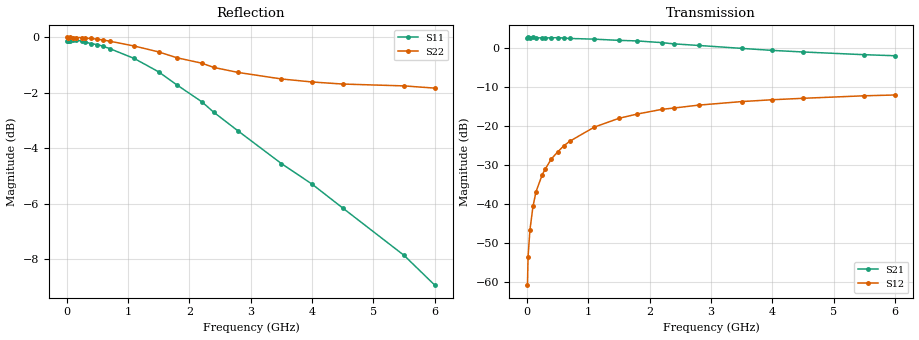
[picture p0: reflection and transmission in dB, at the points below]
! SIEMENS Discrete & RF Semiconductors
! BFY180
! Si NPN RF Bipolar Junction Transistor in MICRO-X
! VCE = 5 V  IC = 0.4 mA
! Common Emitter S-Parameters:  May  1997
# GHz  S  MA  R  50
!  f  S11  S21  S12  S22
! GHz  MAG  ANG  MAG  ANG  MAG  ANG  MAG  ANG
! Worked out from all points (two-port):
!   36 points, 10 MHz to 6 GHz, reference 50 ohm
!   highest |S21| = 2.85 dB at 100 MHz (marker M1); lowest = -1.9 dB at 6 GHz (marker M2)
!   |S21| within 3 dB of the highest: start of sweep to 3.664 GHz
!   lowest |S11| = -8.9 dB at 6 GHz (marker M3), VSWR 2.11, Z = 27.7 - j17.8 ohm
!   |S11| at or under -10 dB: nowhere
!   |S22| runs from -1.8 to 0.0 dB; largest |S21 - S12| = 1.4
!   S11 on the Smith chart (normalised r, x): 10 MHz: open; 700 MHz: 0.71, -5.36; 1.5 GHz: 0.52, -2.45; 2.4 GHz: 0.50, -1.44; 4 GHz: 0.51, -0.79; 6 GHz: 0.55, -0.36
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0.01  0.9844 -0.3  1.378 179.7  0.0009 80.4  0.9995 -0.1
0.02  0.9862 -0.6  1.386 179.0  0.0021 92.9  0.9991 -0.4
0.05  0.9845 -1.5  1.374 178.1  0.0046 87.4  0.9996 -1.1
0.1  0.9873 -3.0  1.388 176.4  0.0093 88.4  0.9979 -2.2
0.15  0.99 -4.6  1.367 174.4  0.0144 87.1  0.999 -3.3
0.25  0.9836 -7.6  1.371 170.7  0.0236 84.2  0.9989 -5.5
0.3  0.9808 -8.8  1.367 168.3  0.0281 83.5  0.9961 -6.5
0.4  0.9737 -11.8  1.369 164.4  0.0379 80.7  0.9953 -8.5
0.5  0.9703 -14.9  1.378 160.4  0.0464 78.2  0.992 -10.8
0.6  0.9631 -17.7  1.36 156.2  0.0556 75.9  0.9889 -12.9
0.7  0.9543 -20.8  1.345 153.1  0.064 73.3  0.984 -15.1
1.1  0.9161 -31.9  1.317 138.4  0.0972 64.2  0.9646 -23.3
1.5  0.8664 -42.9  1.271 124.4  0.1261 55.4  0.9411 -31.2
1.8  0.8202 -51.3  1.249 113.9  0.1433 49.8  0.9184 -36.7
2.2  0.7657 -60.5  1.189 100.8  0.1644 42.4  0.8983 -43.6
2.4  0.7324 -65.2  1.145 94.6  0.1713 39.1  0.8823 -46.8
2.8  0.6772 -73.3  1.093 83.4  0.1865 33.3  0.8641 -52.7
3.5  0.5922 -85.9  1.002 65.1  0.2071 24.4  0.8412 -62.4
4  0.5437 -94.2  0.944 53.6  0.2187 18.7  0.8307 -69.2
4.5  0.4924 -102.0  0.901 43.4  0.2283 13.7  0.8236 -76.0
5.5  0.4045 -118.6  0.831 24.0  0.2459 3.8  0.8173 -90.0
6  0.3575 -128.4  0.806 15.2  0.2518 -1.2  0.8098 -97.0
